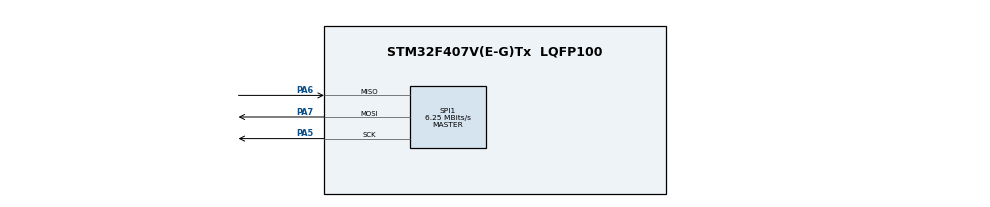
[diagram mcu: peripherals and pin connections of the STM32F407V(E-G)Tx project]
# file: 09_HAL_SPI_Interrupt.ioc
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Mcu.Family=STM32F4
Mcu.Name=STM32F407V(E-G)Tx
Mcu.Package=LQFP100
NVIC.PriorityGroup=NVIC_PRIORITYGROUP_0
NVIC.SPI1_IRQn=true\:0\:0\:false\:false\:true\:true\:true\:true
PA5.Mode=Full_Duplex_Master
PA5.Signal=SPI1_SCK
PA6.Mode=Full_Duplex_Master
PA6.Signal=SPI1_MISO
PA7.Mode=Full_Duplex_Master
PA7.Signal=SPI1_MOSI
PH0-OSC_IN.Mode=HSE-External-Oscillator
PH0-OSC_IN.Signal=RCC_OSC_IN
PH1-OSC_OUT.Mode=HSE-External-Oscillator
PH1-OSC_OUT.Signal=RCC_OSC_OUT
ProjectManager.HeapSize=0x200
ProjectManager.StackSize=0x400
ProjectManager.TargetToolchain=STM32CubeIDE
RCC.48MHZClocksFreq_Value=14285714.285714285
RCC.AHBFreq_Value=25000000
RCC.APB1CLKDivider=RCC_HCLK_DIV4
RCC.APB1Freq_Value=6250000
RCC.APB1TimFreq_Value=12500000
RCC.APB2CLKDivider=RCC_HCLK_DIV2
RCC.APB2Freq_Value=12500000
RCC.APB2TimFreq_Value=25000000
RCC.CortexFreq_Value=25000000
RCC.HCLKFreq_Value=25000000
RCC.HSE_VALUE=8000000
RCC.HSI_VALUE=16000000
RCC.LSE_VALUE=32768
RCC.PLLM=8
RCC.PLLN=50
RCC.PLLP=RCC_PLLP_DIV4
RCC.PLLQ=7
RCC.SYSCLKFreq_VALUE=25000000
RCC.SYSCLKSource=RCC_SYSCLKSOURCE_PLLCLK
RCC.VCOOutputFreq_Value=100000000
SPI1.CalculateBaudRate=6.25 MBits/s
SPI1.Direction=SPI_DIRECTION_2LINES
SPI1.Mode=SPI_MODE_MASTER
SPI1.VirtualType=VM_MASTER
board=STM32F407G-DISC1

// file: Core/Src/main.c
/* USER CODE BEGIN Header */
/**
  ******************************************************************************
  * @file           : main.c
  * @brief          : Main program body
  ******************************************************************************
  * @attention
  *
  * Copyright (c) 2026 STMicroelectronics.
  * All rights reserved.
  *
  * This software is licensed under terms that can be found in the LICENSE file
  * in the root directory of this software component.
  * If no LICENSE file comes with this software, it is provided AS-IS.
  *
  ******************************************************************************
  */
/* USER CODE END Header */
#include "main.h"

SPI_HandleTypeDef hspi1;

/* USER CODE BEGIN PV */
uint8_t tx_data[] = "HELLO";

uint8_t rx_data[10];

/* USER CODE END PV */

void SystemClock_Config(void);
static void MX_GPIO_Init(void);
static void MX_SPI1_Init(void);

int main(void)
{
  /* MCU Configuration--------------------------------------------------------*/
  /* Reset of all peripherals, Initializes the Flash interface and the Systick. */
  HAL_Init();

  /* Configure the system clock */
  SystemClock_Config();
  /* Initialize all configured peripherals */
  MX_GPIO_Init();
  MX_SPI1_Init();
  /* USER CODE BEGIN 2 */
  HAL_SPI_TransmitReceive_IT(&hspi1, tx_data, rx_data, 5);
  /* USER CODE END 2 */
  /* Infinite loop */
  while (1)
  {
  }
}

void SystemClock_Config(void)
{
  RCC_OscInitTypeDef RCC_OscInitStruct = {0};
  RCC_ClkInitTypeDef RCC_ClkInitStruct = {0};

  /** Configure the main internal regulator output voltage
  */
  __HAL_RCC_PWR_CLK_ENABLE();
  __HAL_PWR_VOLTAGESCALING_CONFIG(PWR_REGULATOR_VOLTAGE_SCALE1);

  /** Initializes the RCC Oscillators according to the specified parameters
  * in the RCC_OscInitTypeDef structure.
  */
  RCC_OscInitStruct.OscillatorType = RCC_OSCILLATORTYPE_HSE;
  RCC_OscInitStruct.HSEState = RCC_HSE_ON;
  RCC_OscInitStruct.PLL.PLLState = RCC_PLL_ON;
  RCC_OscInitStruct.PLL.PLLSource = RCC_PLLSOURCE_HSE;
  RCC_OscInitStruct.PLL.PLLM = 8;
  RCC_OscInitStruct.PLL.PLLN = 336;
  RCC_OscInitStruct.PLL.PLLP = RCC_PLLP_DIV2;
  RCC_OscInitStruct.PLL.PLLQ = 7;
  if (HAL_RCC_OscConfig(&RCC_OscInitStruct) != HAL_OK)
  {
    Error_Handler();
  }

  /** Initializes the CPU, AHB and APB buses clocks
  */
  RCC_ClkInitStruct.ClockType = RCC_CLOCKTYPE_HCLK|RCC_CLOCKTYPE_SYSCLK
                              |RCC_CLOCKTYPE_PCLK1|RCC_CLOCKTYPE_PCLK2;
  RCC_ClkInitStruct.SYSCLKSource = RCC_SYSCLKSOURCE_PLLCLK;
  RCC_ClkInitStruct.AHBCLKDivider = RCC_SYSCLK_DIV1;
  RCC_ClkInitStruct.APB1CLKDivider = RCC_HCLK_DIV4;
  RCC_ClkInitStruct.APB2CLKDivider = RCC_HCLK_DIV2;

  if (HAL_RCC_ClockConfig(&RCC_ClkInitStruct, FLASH_LATENCY_5) != HAL_OK)
  {
    Error_Handler();
  }
}

static void MX_SPI1_Init(void)
{

  /* SPI1 parameter configuration*/
  hspi1.Instance = SPI1;
  hspi1.Init.Mode = SPI_MODE_MASTER;
  hspi1.Init.Direction = SPI_DIRECTION_2LINES;
  hspi1.Init.DataSize = SPI_DATASIZE_8BIT;
  hspi1.Init.CLKPolarity = SPI_POLARITY_LOW;
  hspi1.Init.CLKPhase = SPI_PHASE_1EDGE;
  hspi1.Init.NSS = SPI_NSS_SOFT;
  hspi1.Init.BaudRatePrescaler = SPI_BAUDRATEPRESCALER_2;
  hspi1.Init.FirstBit = SPI_FIRSTBIT_MSB;
  hspi1.Init.TIMode = SPI_TIMODE_DISABLE;
  hspi1.Init.CRCCalculation = SPI_CRCCALCULATION_DISABLE;
  hspi1.Init.CRCPolynomial = 10;
  if (HAL_SPI_Init(&hspi1) != HAL_OK)
  {
    Error_Handler();
  }

}

static void MX_GPIO_Init(void)
{
  GPIO_InitTypeDef GPIO_InitStruct = {0};

  /* GPIO Ports Clock Enable */
  __HAL_RCC_GPIOH_CLK_ENABLE();
  __HAL_RCC_GPIOA_CLK_ENABLE();
  __HAL_RCC_GPIOD_CLK_ENABLE();

  /*Configure GPIO pin Output Level */
  HAL_GPIO_WritePin(GPIOD, GPIO_PIN_12, GPIO_PIN_RESET);

  /*Configure GPIO pin : PD12 */
  GPIO_InitStruct.Pin = GPIO_PIN_12;
  GPIO_InitStruct.Mode = GPIO_MODE_OUTPUT_PP;
  GPIO_InitStruct.Pull = GPIO_NOPULL;
  GPIO_InitStruct.Speed = GPIO_SPEED_FREQ_LOW;
  HAL_GPIO_Init(GPIOD, &GPIO_InitStruct);

}

/* USER CODE BEGIN 4 */
void HAL_SPI_TxRxCpltCallback(SPI_HandleTypeDef *hspi)
{
    if(hspi->Instance == SPI1)
    {
        HAL_GPIO_TogglePin(GPIOD,
                           GPIO_PIN_12);

        //HAL_Delay(1000);

        HAL_SPI_TransmitReceive_IT(&hspi1, tx_data, rx_data, 5);
    }
}

/* USER CODE END 4 */

void Error_Handler(void)
{
  __disable_irq();
  while (1)
  {
  }
}
